VERSION 5.7 ;
  NOWIREEXTENSIONATPIN ON ;
  DIVIDERCHAR "/" ;
  BUSBITCHARS "[]" ;
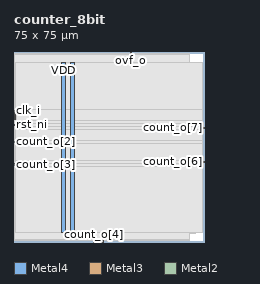
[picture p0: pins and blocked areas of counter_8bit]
MACRO counter_8bit
  CLASS BLOCK ;
  FOREIGN counter_8bit ;
  ORIGIN 0.000 0.000 ;
  SIZE 75.000 BY 75.000 ;
  PIN VDD
    DIRECTION INOUT ;
    USE POWER ;
    PORT
      LAYER Metal4 ;
        RECT 18.880 3.620 20.480 70.860 ;
    END
  END VDD
  PIN VSS
    DIRECTION INOUT ;
    USE GROUND ;
    PORT
      LAYER Metal4 ;
        RECT 22.180 3.620 23.780 70.860 ;
    END
  END VSS
  PIN clk_i
    DIRECTION INPUT ;
    USE SIGNAL ;
    ANTENNAGATEAREA 4.738000 ;
    PORT
      LAYER Metal3 ;
        RECT 0.000 51.520 0.560 52.080 ;
    END
  END clk_i
  PIN count_o[0]
    DIRECTION OUTPUT ;
    USE SIGNAL ;
    ANTENNADIFFAREA 0.897600 ;
    PORT
      LAYER Metal3 ;
        RECT 0.000 50.400 0.560 50.960 ;
    END
  END count_o[0]
  PIN count_o[1]
    DIRECTION OUTPUT ;
    USE SIGNAL ;
    ANTENNADIFFAREA 0.897600 ;
    PORT
      LAYER Metal3 ;
        RECT 0.000 49.280 0.560 49.840 ;
    END
  END count_o[1]
  PIN count_o[2]
    DIRECTION OUTPUT ;
    USE SIGNAL ;
    ANTENNADIFFAREA 0.897600 ;
    PORT
      LAYER Metal3 ;
        RECT 0.000 39.200 0.560 39.760 ;
    END
  END count_o[2]
  PIN count_o[3]
    DIRECTION OUTPUT ;
    USE SIGNAL ;
    ANTENNADIFFAREA 0.897600 ;
    PORT
      LAYER Metal3 ;
        RECT 0.000 30.240 0.560 30.800 ;
    END
  END count_o[3]
  PIN count_o[4]
    DIRECTION OUTPUT ;
    USE SIGNAL ;
    ANTENNADIFFAREA 0.897600 ;
    PORT
      LAYER Metal2 ;
        RECT 31.360 0.000 31.920 0.560 ;
    END
  END count_o[4]
  PIN count_o[5]
    DIRECTION OUTPUT ;
    USE SIGNAL ;
    ANTENNADIFFAREA 0.897600 ;
    PORT
      LAYER Metal2 ;
        RECT 34.720 0.000 35.280 0.560 ;
    END
  END count_o[5]
  PIN count_o[6]
    DIRECTION OUTPUT ;
    USE SIGNAL ;
    ANTENNADIFFAREA 0.897600 ;
    PORT
      LAYER Metal3 ;
        RECT 74.440 31.360 75.000 31.920 ;
    END
  END count_o[6]
  PIN count_o[7]
    DIRECTION OUTPUT ;
    USE SIGNAL ;
    ANTENNADIFFAREA 0.897600 ;
    PORT
      LAYER Metal3 ;
        RECT 74.440 44.800 75.000 45.360 ;
    END
  END count_o[7]
  PIN en_i
    DIRECTION INPUT ;
    USE SIGNAL ;
    ANTENNAGATEAREA 0.396000 ;
    PORT
      LAYER Metal3 ;
        RECT 0.000 48.160 0.560 48.720 ;
    END
  END en_i
  PIN ovf_o
    DIRECTION OUTPUT ;
    USE SIGNAL ;
    ANTENNADIFFAREA 0.897600 ;
    PORT
      LAYER Metal2 ;
        RECT 45.920 74.440 46.480 75.000 ;
    END
  END ovf_o
  PIN rst_ni
    DIRECTION INPUT ;
    USE SIGNAL ;
    ANTENNAGATEAREA 0.396000 ;
    PORT
      LAYER Metal3 ;
        RECT 0.000 45.920 0.560 46.480 ;
    END
  END rst_ni
  OBS
      LAYER Nwell ;
        RECT 2.930 3.490 71.550 70.990 ;
      LAYER Metal1 ;
        RECT 3.360 3.620 71.120 70.860 ;
      LAYER Metal2 ;
        RECT 0.140 74.140 45.620 74.440 ;
        RECT 46.780 74.140 69.300 74.440 ;
        RECT 0.140 0.860 69.300 74.140 ;
        RECT 0.140 0.560 31.060 0.860 ;
        RECT 32.220 0.560 34.420 0.860 ;
        RECT 35.580 0.560 69.300 0.860 ;
      LAYER Metal3 ;
        RECT 0.560 52.380 74.440 70.700 ;
        RECT 0.860 47.860 74.440 52.380 ;
        RECT 0.560 46.780 74.440 47.860 ;
        RECT 0.860 45.660 74.440 46.780 ;
        RECT 0.860 45.620 74.140 45.660 ;
        RECT 0.560 44.500 74.140 45.620 ;
        RECT 0.560 40.060 74.440 44.500 ;
        RECT 0.860 38.900 74.440 40.060 ;
        RECT 0.560 32.220 74.440 38.900 ;
        RECT 0.560 31.100 74.140 32.220 ;
        RECT 0.860 31.060 74.140 31.100 ;
        RECT 0.860 29.940 74.440 31.060 ;
        RECT 0.560 3.780 74.440 29.940 ;
  END
END counter_8bit
END LIBRARY

